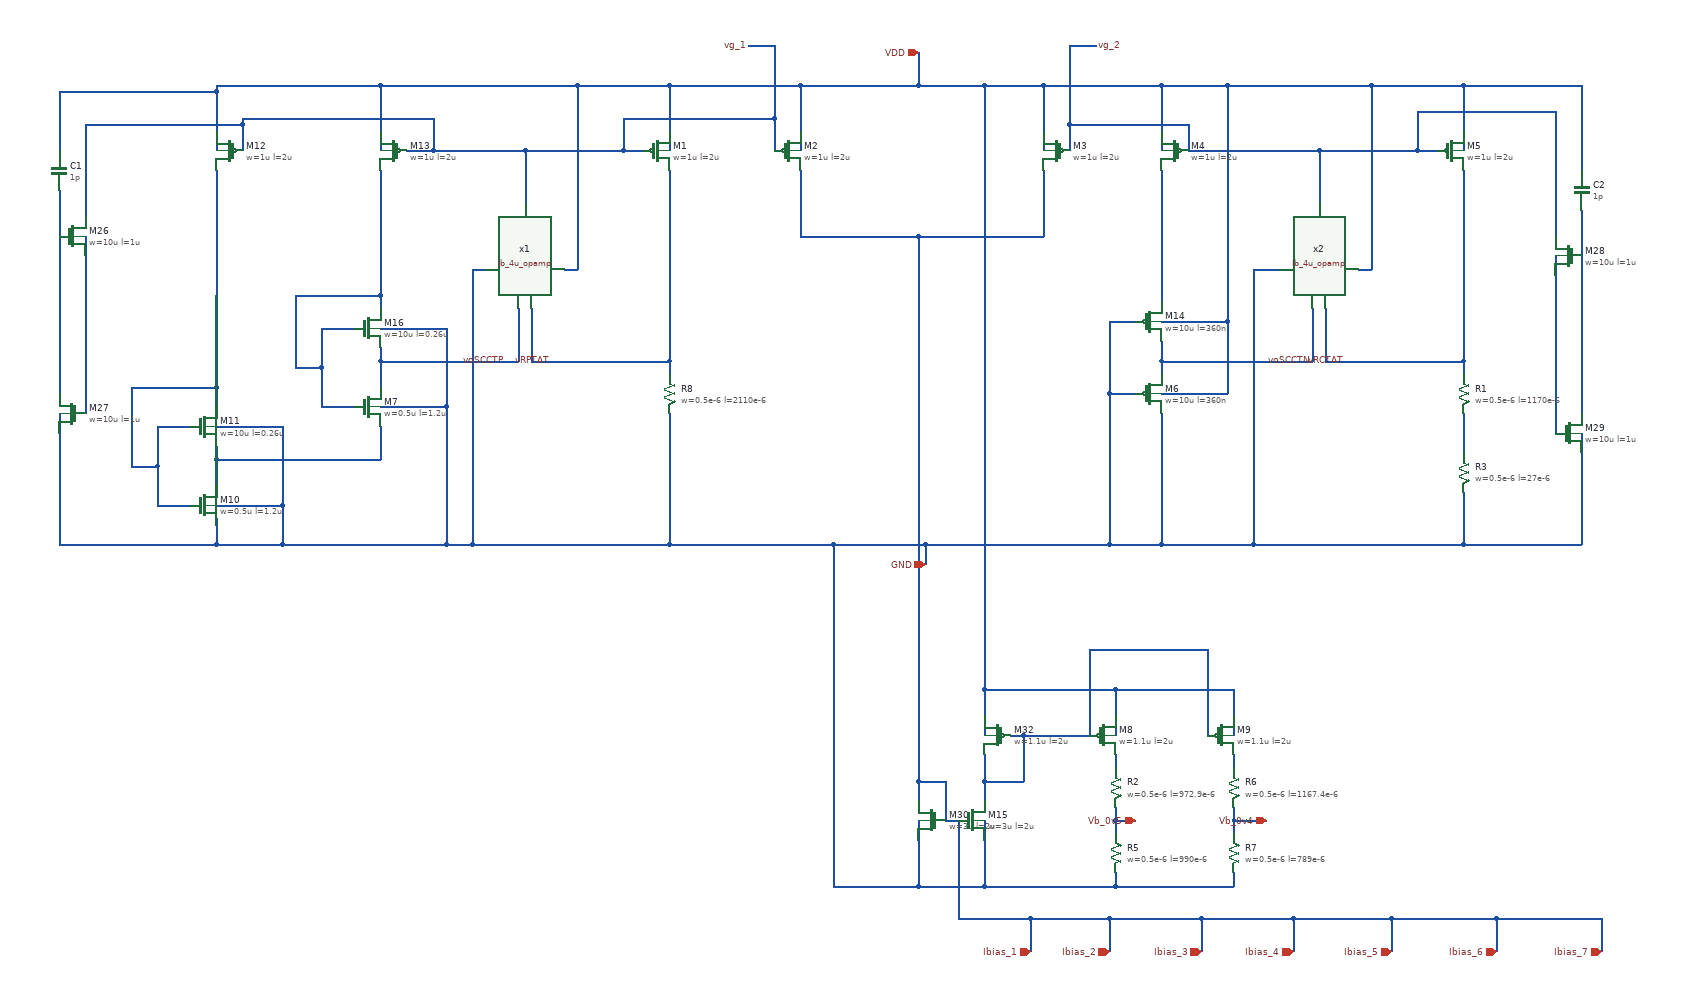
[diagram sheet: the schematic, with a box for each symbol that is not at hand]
v {xschem version=3.4.6 file_version=1.2}
G {}
K {}
V {}
S {}
E {}
N 1770 -1030 1770 -990 {lab=vg_2}
N 1650 -730 1690 -730 {lab=GND}
N 1650 -620 1690 -620 {lab=GND}
N 1730 -670 1730 -650 {lab=voSCCTN}
N 1970 -990 1970 -910 {lab=vg_2}
N 1770 -990 1970 -990 {lab=vg_2}
N 1180 -1090 1180 -990 {lab=VDD}
N 1550 -1090 1550 -990 {lab=VDD}
N 1730 -1090 1730 -990 {lab=VDD}
N 2190 -1090 2190 -990 {lab=VDD}
N 290 -1090 540 -1090 {lab=VDD}
N 980 -1090 980 -990 {lab=VDD}
N 840 -1090 980 -1090 {lab=VDD}
N 910 -990 940 -990 {lab=vg_1}
N 910 -1040 910 -990 {lab=vg_1}
N 1140 -1040 1140 -990 {lab=vg_1}
N 1590 -1030 1590 -990 {lab=vg_2}
N 760 -990 910 -990 {lab=vg_1}
N 540 -1090 540 -990 {lab=VDD}
N 760 -990 760 -910 {lab=vg_1}
N 620 -990 760 -990 {lab=vg_1}
N 820 -810 840 -810 {lab=VDD}
N 840 -1090 840 -810 {lab=VDD}
N 540 -1090 840 -1090 {lab=VDD}
N 540 -670 540 -630 {lab=voSCCTP}
N 540 -720 640 -720 {lab=GND}
N 640 -720 640 -600 {lab=GND}
N 540 -600 640 -600 {lab=GND}
N 450 -720 500 -720 {lab=#net1}
N 450 -660 450 -600 {lab=#net1}
N 450 -600 500 -600 {lab=#net1}
N 540 -770 540 -750 {lab=#net1}
N 410 -660 450 -660 {lab=#net1}
N 450 -720 450 -660 {lab=#net1}
N 410 -770 410 -660 {lab=#net1}
N 410 -770 540 -770 {lab=#net1}
N 540 -960 540 -770 {lab=#net1}
N 540 -670 750 -670 {lab=voSCCTP}
N 540 -690 540 -670 {lab=voSCCTP}
N 750 -750 750 -670 {lab=voSCCTP}
N 290 -520 290 -480 {lab=#net2}
N 290 -570 390 -570 {lab=GND}
N 390 -570 390 -450 {lab=GND}
N 290 -450 390 -450 {lab=GND}
N 200 -570 250 -570 {lab=#net3}
N 200 -510 200 -450 {lab=#net3}
N 200 -450 250 -450 {lab=#net3}
N 160 -510 200 -510 {lab=#net3}
N 200 -570 200 -510 {lab=#net3}
N 290 -520 540 -520 {lab=#net2}
N 290 -540 290 -520 {lab=#net2}
N 540 -570 540 -520 {lab=#net2}
N 290 -630 290 -600 {lab=#net3}
N 290 -1080 290 -990 {lab=VDD}
N 330 -1030 330 -990 {lab=vg_1}
N 330 -1040 620 -1040 {lab=vg_1}
N 620 -1040 620 -990 {lab=vg_1}
N 580 -990 620 -990 {lab=vg_1}
N 290 -430 290 -390 {lab=GND}
N 160 -630 160 -510 {lab=#net3}
N 160 -630 290 -630 {lab=#net3}
N 290 -960 290 -630 {lab=#net3}
N 1650 -730 1650 -620 {lab=GND}
N 640 -600 640 -390 {lab=GND}
N 390 -390 640 -390 {lab=GND}
N 390 -450 390 -390 {lab=GND}
N 290 -390 390 -390 {lab=GND}
N 1730 -620 1830 -620 {lab=VDD}
N 2050 -1090 2190 -1090 {lab=VDD}
N 980 -670 980 -650 {lab=vRPTAT}
N 980 -590 980 -390 {lab=GND}
N 680 -390 980 -390 {lab=GND}
N 770 -750 770 -670 {lab=vRPTAT}
N 770 -670 980 -670 {lab=vRPTAT}
N 980 -960 980 -670 {lab=vRPTAT}
N 2190 -670 2190 -650 {lab=vRCTAT}
N 1980 -670 2190 -670 {lab=vRCTAT}
N 2190 -960 2190 -670 {lab=vRCTAT}
N 1980 -750 1980 -670 {lab=vRCTAT}
N 1960 -750 1960 -670 {lab=voSCCTN}
N 1730 -960 1730 -760 {lab=#net4}
N 1730 -590 1730 -390 {lab=GND}
N 1730 -670 1960 -670 {lab=voSCCTN}
N 1730 -700 1730 -670 {lab=voSCCTN}
N 1830 -730 1830 -620 {lab=VDD}
N 1730 -1090 1830 -1090 {lab=VDD}
N 1870 -810 1910 -810 {lab=GND}
N 1870 -810 1870 -390 {lab=GND}
N 1730 -390 1870 -390 {lab=GND}
N 2030 -810 2050 -810 {lab=VDD}
N 2050 -1090 2050 -810 {lab=VDD}
N 1830 -1090 2050 -1090 {lab=VDD}
N 1650 -390 1730 -390 {lab=GND}
N 1650 -620 1650 -390 {lab=GND}
N 1590 -1030 1770 -1030 {lab=vg_2}
N 910 -1040 1140 -1040 {lab=vg_1}
N 980 -1090 1180 -1090 {lab=VDD}
N 1550 -1090 1730 -1090 {lab=VDD}
N 1460 -1090 1550 -1090 {lab=VDD}
N 680 -810 700 -810 {lab=GND}
N 680 -810 680 -390 {lab=GND}
N 1730 -730 1830 -730 {lab=VDD}
N 1830 -1090 1830 -730 {lab=VDD}
N 1360 -860 1550 -860 {lab=Ibias_1}
N 1180 -960 1180 -860 {lab=Ibias_1}
N 1550 -960 1550 -860 {lab=Ibias_1}
N 1180 -860 1360 -860 {lab=Ibias_1}
N 1360 -1140 1360 -1090 {lab=VDD}
N 1180 -1090 1360 -1090 {lab=VDD}
N 1370 -390 1650 -390 {lab=GND}
N 1370 -390 1370 -360 {lab=GND}
N 1230 -390 1370 -390 {lab=GND}
N 1140 -1150 1140 -1040 {lab=vg_1}
N 1100 -1150 1140 -1150 {lab=vg_1}
N 1590 -1150 1630 -1150 {lab=vg_2}
N 1590 -1150 1590 -1030 {lab=vg_2}
N 2120 -990 2150 -990 {lab=vg_2}
N 1230 -390 1230 130 {lab=GND}
N 980 -390 1230 -390 {lab=GND}
N 1360 30 1360 130 {lab=GND}
N 1360 -30 1360 -0 {lab=Ibias_1}
N 1400 30 1420 30 {lab=Ibias_1}
N 1230 130 1360 130 {lab=GND}
N 1360 -1090 1460 -1090 {lab=VDD}
N 1400 -30 1400 30 {lab=Ibias_1}
N 1360 -30 1400 -30 {lab=Ibias_1}
N 1360 -860 1360 -30 {lab=Ibias_1}
N 1460 -30 1460 -0 {lab=#net5}
N 1360 130 1460 130 {lab=GND}
N 1460 30 1460 130 {lab=GND}
N 2240 180 2240 230 {lab=Ibias_1}
N 2080 180 2080 230 {lab=Ibias_1}
N 1930 180 1930 230 {lab=Ibias_1}
N 1790 180 1790 230 {lab=Ibias_1}
N 1650 180 1650 230 {lab=Ibias_1}
N 1460 -170 1460 -100 {lab=VDD}
N 1460 -30 1520 -30 {lab=#net5}
N 1460 -70 1460 -30 {lab=#net5}
N 1520 -100 1520 -30 {lab=#net5}
N 1500 -100 1520 -100 {lab=#net5}
N 1660 -70 1660 -50 {lab=#net6}
N 1660 110 1660 130 {lab=GND}
N 1660 30 1660 50 {lab=Vb_0v5}
N 1660 30 1690 30 {lab=Vb_0v5}
N 1660 10 1660 30 {lab=Vb_0v5}
N 1840 -70 1840 -50 {lab=#net7}
N 1840 30 1840 50 {lab=Vb_0v4}
N 1660 130 1840 130 {lab=GND}
N 1840 110 1840 130 {lab=GND}
N 1840 30 1890 30 {lab=Vb_0v4}
N 1840 10 1840 30 {lab=Vb_0v4}
N 2190 -590 2190 -530 {lab=#net8}
N 2190 -470 2190 -390 {lab=GND}
N 2400 180 2400 230 {lab=Ibias_1}
N 1660 -170 1840 -170 {lab=VDD}
N 1840 -170 1840 -100 {lab=VDD}
N 1620 -230 1620 -100 {lab=#net5}
N 1800 -230 1800 -100 {lab=#net5}
N 1660 -170 1660 -100 {lab=VDD}
N 640 -390 680 -390 {lab=GND}
N 1870 -390 2190 -390 {lab=GND}
N 50 -590 50 -390 {lab=GND}
N 50 -930 50 -620 {lab=#net9}
N 50 -1080 50 -990 {lab=VDD}
N 90 -1030 90 -890 {lab=vg_1}
N 90 -860 90 -590 {lab=#net10}
N 50 -390 290 -390 {lab=GND}
N 50 -1080 290 -1080 {lab=VDD}
N 290 -1090 290 -1080 {lab=VDD}
N 330 -1040 330 -1030 {lab=vg_1}
N 90 -1030 330 -1030 {lab=vg_1}
N 2370 -560 2370 -390 {lab=GND}
N 2370 -900 2370 -590 {lab=#net11}
N 2330 -830 2330 -560 {lab=#net12}
N 2190 -390 2370 -390 {lab=GND}
N 2370 -1090 2370 -960 {lab=VDD}
N 2190 -1090 2370 -1090 {lab=VDD}
N 2330 -1050 2330 -860 {lab=vg_2}
N 2120 -1050 2330 -1050 {lab=vg_2}
N 2120 -1050 2120 -990 {lab=vg_2}
N 1970 -990 2120 -990 {lab=vg_2}
N 1420 30 1420 180 {lab=Ibias_1}
N 1530 180 1650 180 {lab=Ibias_1}
N 2080 180 2240 180 {lab=Ibias_1}
N 1930 180 2080 180 {lab=Ibias_1}
N 1790 180 1930 180 {lab=Ibias_1}
N 1650 180 1790 180 {lab=Ibias_1}
N 2240 180 2400 180 {lab=Ibias_1}
N 1530 180 1530 230 {lab=Ibias_1}
N 1420 180 1530 180 {lab=Ibias_1}
N 1520 -100 1620 -100 {lab=#net5}
N 1620 -230 1800 -230 {lab=#net5}
N 1460 -170 1660 -170 {lab=VDD}
N 1460 -1090 1460 -170 {lab=VDD}
N 1460 130 1660 130 {lab=GND}
C {iopin.sym} 1360 -1140 0 0 {name=p1 lab=VDD}
C {iopin.sym} 1370 -360 0 0 {name=p2 lab=GND}
C {iopin.sym} 1530 230 0 0 {name=p3 lab=Ibias_1}
C {lab_pin.sym} 730 -670 3 0 {name=p9 sig_type=std_logic lab=voSCCTP}
C {lab_pin.sym} 1960 -670 3 0 {name=p10 sig_type=std_logic lab=voSCCTN}
C {lab_pin.sym} 2010 -670 3 0 {name=p11 sig_type=std_logic lab=vRCTAT}
C {lab_pin.sym} 800 -670 3 0 {name=p12 sig_type=std_logic lab=vRPTAT}
C {sg13g2_pr/sg13_lv_pmos.sym} 960 -990 0 0 {name=M1
l=2u
w=1u
ng=1
m=1
model=sg13_lv_pmos
spiceprefix=X
}
C {sg13g2_pr/sg13_lv_pmos.sym} 1160 -990 0 0 {name=M2
l=2u
w=1u
ng=1
m=6
model=sg13_lv_pmos
spiceprefix=X
}
C {sg13g2_pr/sg13_lv_pmos.sym} 1570 -990 0 1 {name=M3
l=2u
w=1u
ng=1
m=6
model=sg13_lv_pmos
spiceprefix=X
}
C {sg13g2_pr/sg13_lv_pmos.sym} 1750 -990 0 1 {name=M4
l=2u
w=1u
ng=1
m=1
model=sg13_lv_pmos
spiceprefix=X
}
C {sg13g2_pr/sg13_lv_pmos.sym} 310 -990 0 1 {name=M12
l=2u
w=1u
ng=1
m=1
model=sg13_lv_pmos
spiceprefix=X
}
C {sg13g2_pr/sg13_lv_pmos.sym} 560 -990 0 1 {name=M13
l=2u
w=1u
ng=1
m=1
model=sg13_lv_pmos
spiceprefix=X
}
C {sg13g2_pr/sg13_lv_pmos.sym} 2170 -990 0 0 {name=M5
l=2u
w=1u
ng=1
m=1
model=sg13_lv_pmos
spiceprefix=X
}
C {sg13g2_pr/sg13_lv_nmos.sym} 520 -600 0 0 {name=M7
l=1.2u
w=0.5u
ng=1
m=1
model=sg13_lv_nmos
spiceprefix=X
}
C {sg13g2_pr/sg13_lv_nmos.sym} 270 -450 0 0 {name=M10
l=1.2u
w=0.5u
ng=1
m=1
model=sg13_lv_nmos
spiceprefix=X
}
C {sg13g2_pr/sg13_lv_nmos.sym} 270 -570 0 0 {name=M11
l=0.26u
w=10u
ng=1
m=30
model=sg13_lv_nmos
spiceprefix=X
}
C {sg13g2_pr/sg13_lv_nmos.sym} 520 -720 0 0 {name=M16
l=0.26u
w=10u
ng=1
m=30
model=sg13_lv_nmos
spiceprefix=X
}
C {sg13g2_pr/sg13_lv_pmos.sym} 1710 -620 0 0 {name=M6
l=360n
w=10u
ng=1
m=20
model=sg13_lv_pmos
spiceprefix=X
}
C {sg13g2_pr/sg13_lv_pmos.sym} 1710 -730 0 0 {name=M14
l=360n
w=10u
ng=1
m=1
model=sg13_lv_pmos
spiceprefix=X
}
C {iopin.sym} 1650 230 0 0 {name=p4 lab=Ibias_2}
C {iopin.sym} 1790 230 0 0 {name=p5 lab=Ibias_3}
C {iopin.sym} 1930 230 0 0 {name=p6 lab=Ibias_4}
C {iopin.sym} 2080 230 0 0 {name=p7 lab=Ibias_5}
C {iopin.sym} 2240 230 0 0 {name=p8 lab=Ibias_6}
C {lab_pin.sym} 1100 -1150 0 0 {name=p14 sig_type=std_logic lab=vg_1}
C {lab_pin.sym} 1630 -1150 0 1 {name=p15 sig_type=std_logic lab=vg_2}
C {/shared/designs/SSDOR_w_startup_1V_ihp/Ib_4u/Ib_4u_opamp/Ib_4u_opamp.sym} 700 -750 1 1 {name=x1}
C {/shared/designs/SSDOR_w_startup_1V_ihp/Ib_4u/Ib_4u_opamp/Ib_4u_opamp.sym} 1910 -750 1 1 {name=x2}
C {sg13g2_pr/sg13_lv_nmos.sym} 1380 30 0 1 {name=M30
l=2u
w=3u
ng=1
m=1
model=sg13_lv_nmos
spiceprefix=X
}
C {sg13g2_pr/sg13_lv_pmos.sym} 1480 -100 0 1 {name=M32
l=2u
w=1.1u
ng=1
m=6
model=sg13_lv_pmos
spiceprefix=X
}
C {sg13g2_pr/sg13_lv_pmos.sym} 1640 -100 0 0 {name=M8
l=2u
w=1.1u
ng=1
m=6
model=sg13_lv_pmos
spiceprefix=X
}
C {sg13g2_pr/rppd.sym} 1660 -20 0 0 {name=R2
w=0.5e-6
l=972.9e-6
model=rppd
body=GND
spiceprefix=X
b=0
m=1
}
C {sg13g2_pr/sg13_lv_pmos.sym} 1820 -100 0 0 {name=M9
l=2u
w=1.1u
ng=1
m=6
model=sg13_lv_pmos
spiceprefix=X
}
C {sg13g2_pr/rppd.sym} 1840 -20 0 0 {name=R6
w=0.5e-6
l=1167.4e-6
model=rppd
body=GND
spiceprefix=X
b=0
m=1
}
C {sg13g2_pr/rppd.sym} 1840 80 0 0 {name=R7
w=0.5e-6
l=789e-6
model=rppd
body=GND
spiceprefix=X
b=0
m=1
}
C {iopin.sym} 1890 30 0 0 {name=p16 lab=Vb_0v4}
C {iopin.sym} 1690 30 0 0 {name=p17 lab=Vb_0v5}
C {sg13g2_pr/rppd.sym} 1660 80 0 0 {name=R5
w=0.5e-6
l=990e-6
model=rppd
body=GND
spiceprefix=X
b=0
m=1
}
C {sg13g2_pr/rppd.sym} 980 -620 0 0 {name=R8
w=0.5e-6
l=2110e-6
model=rppd
body=GND
spiceprefix=X
b=0
m=1
}
C {sg13g2_pr/rppd.sym} 2190 -620 0 0 {name=R1
w=0.5e-6
l=1170e-6
model=rppd
body=GND
spiceprefix=X
b=0
m=1
}
C {sg13g2_pr/rhigh.sym} 2190 -500 0 0 {name=R3
w=0.5e-6
l=27e-6
model=rhigh
body=GND
spiceprefix=X
b=0
m=1
}
C {iopin.sym} 2400 230 0 0 {name=p13 lab=Ibias_7}
C {sg13g2_pr/sg13_lv_nmos.sym} 70 -860 0 0 {name=M26
l=1u
w=10u
ng=1
m=1
model=sg13_lv_nmos
spiceprefix=X
}
C {sg13g2_pr/sg13_lv_nmos.sym} 70 -590 0 1 {name=M27
l=1u
w=10u
ng=1
m=1
model=sg13_lv_nmos
spiceprefix=X
}
C {capa.sym} 50 -960 0 0 {name=C1
m=1
value=1p
footprint=1206
device="ceramic capacitor"}
C {sg13g2_pr/sg13_lv_nmos.sym} 2350 -830 0 1 {name=M28
l=1u
w=10u
ng=1
m=1
model=sg13_lv_nmos
spiceprefix=X
}
C {sg13g2_pr/sg13_lv_nmos.sym} 2350 -560 0 0 {name=M29
l=1u
w=10u
ng=1
m=1
model=sg13_lv_nmos
spiceprefix=X
}
C {capa.sym} 2370 -930 0 1 {name=C2
m=1
value=1p
footprint=1206
device="ceramic capacitor"}
C {sg13g2_pr/sg13_lv_nmos.sym} 1440 30 0 0 {name=M15
l=2u
w=3u
ng=1
m=1
model=sg13_lv_nmos
spiceprefix=X
}
